VERSION 5.8 ;
BUSBITCHARS "[]" ;
DIVIDERCHAR "/" ;
UNITS DATABASE MICRONS 1000 ; END UNITS
MANUFACTURINGGRID 0.001 ;
LAYER M1 TYPE ROUTING ; DIRECTION HORIZONTAL ; PITCH 0.2 ; WIDTH 0.1 ; SPACING 0.1 ; END M1
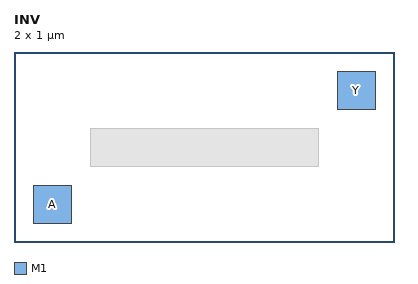
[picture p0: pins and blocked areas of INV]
MACRO INV
 CLASS CORE ; ORIGIN 0 0 ; SIZE 2 BY 1 ;
 PIN A DIRECTION INPUT ; USE SIGNAL ; PORT LAYER M1 ; RECT 0.1 0.1 0.3 0.3 ; END END A
 PIN Y DIRECTION OUTPUT ; USE SIGNAL ; PORT LAYER M1 ; RECT 1.7 0.7 1.9 0.9 ; END END Y
 OBS LAYER M1 ; RECT 0.4 0.4 1.6 0.6 ; END
END INV
END LIBRARY
